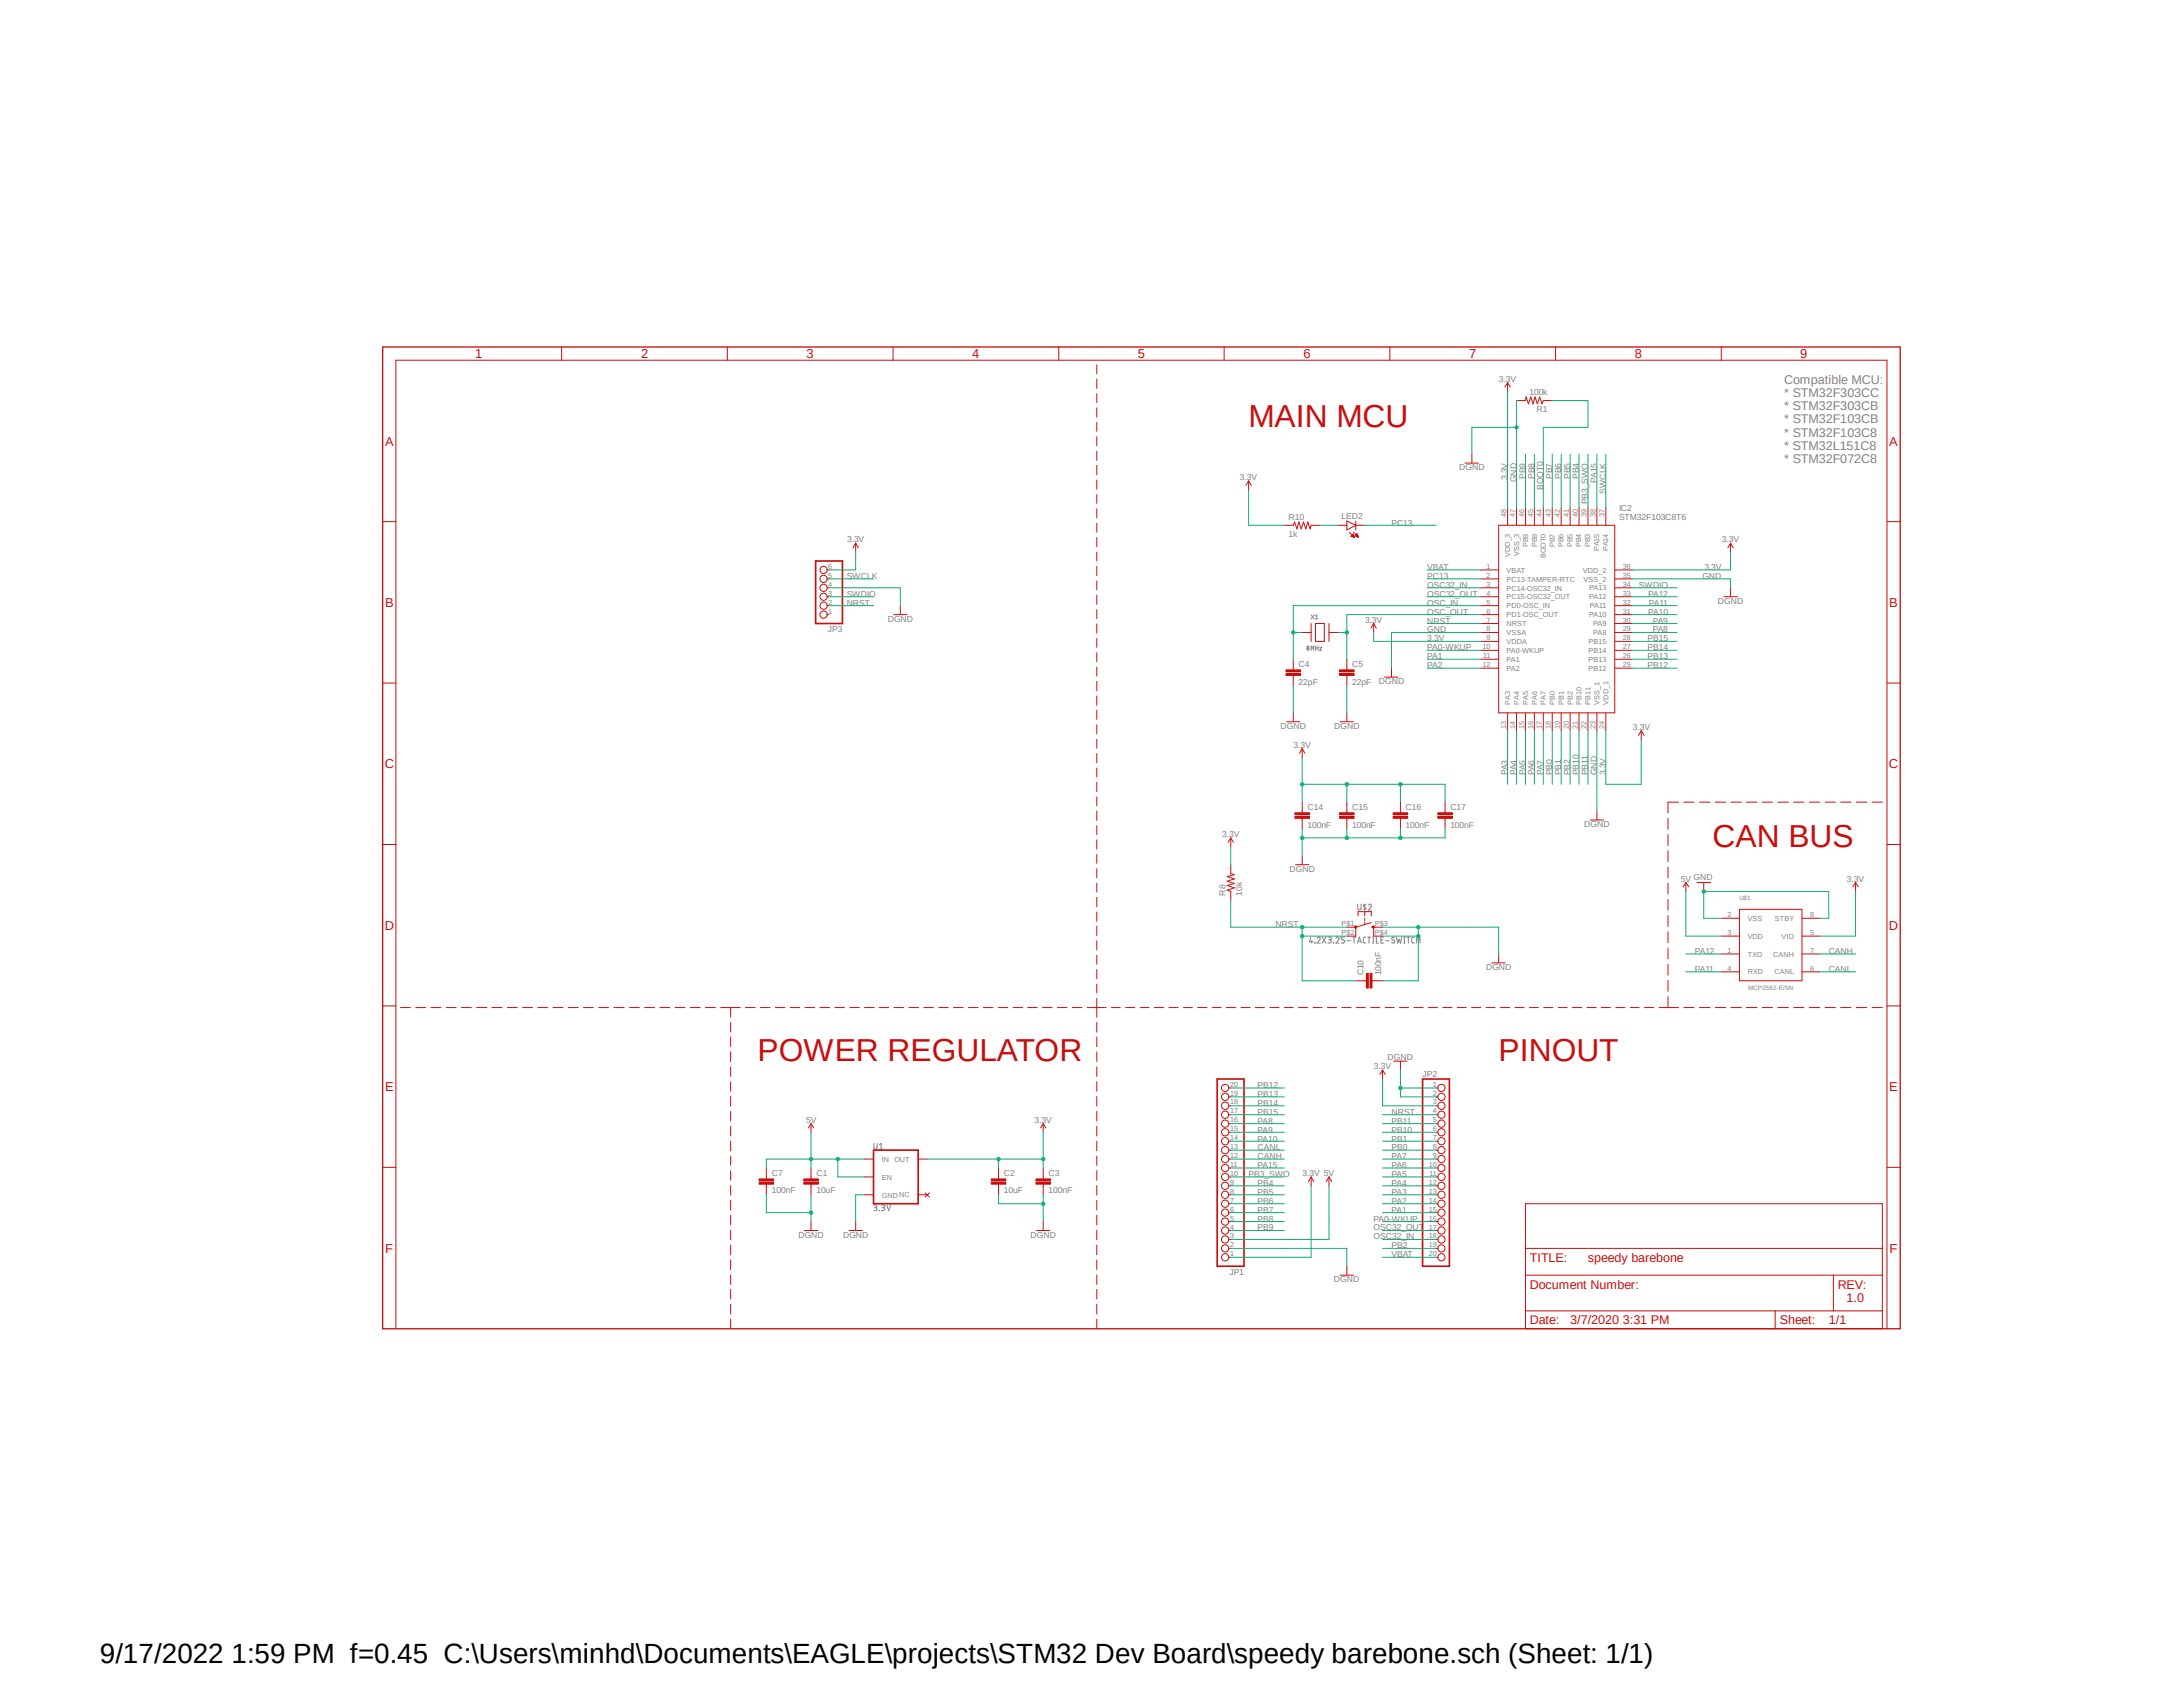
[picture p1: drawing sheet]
<svg xmlns="http://www.w3.org/2000/svg" width="279mm" height="216mm" viewBox="0 0 279 216" stroke-linecap="round" stroke-linejoin="round" font-family="sans-serif">
<defs><g id="words">
<g font-size="4.1" fill="#c90d0c">
<text x="159.8" y="54.7">MAIN MCU</text>
<text x="219.2" y="108.4">CAN BUS</text>
<text x="96.9" y="135.8">POWER REGULATOR</text>
<text x="191.8" y="135.8">PINOUT</text>
</g>
<text font-size="3.6" x="12.8" y="212.9">9/17/2022 1:59 PM f=0.45 C:\Users\minhd\Documents\EAGLE\projects\STM32 Dev Board\speedy barebone.sch (Sheet: 1/1)</text>
<g font-size="1.7" fill="#c90d0c">
<text x="60.8" y="45.8">1</text>
<text x="82" y="45.8">2</text>
<text x="103.2" y="45.8">3</text>
<text x="124.4" y="45.8">4</text>
<text x="145.6" y="45.8">5</text>
<text x="166.8" y="45.8">6</text>
<text x="188" y="45.8">7</text>
<text x="209.3" y="45.8">8</text>
<text x="230.4" y="45.8">9</text>
<text x="49.3" y="57">A</text>
<text x="241.8" y="57">A</text>
<text x="49.3" y="77.7">B</text>
<text x="241.8" y="77.7">B</text>
<text x="49.2" y="98.3">C</text>
<text x="241.8" y="98.3">C</text>
<text x="49.2" y="119">D</text>
<text x="241.8" y="119">D</text>
<text x="49.3" y="139.7">E</text>
<text x="241.8" y="139.7">E</text>
<text x="49.3" y="160.3">F</text>
<text x="241.9" y="160.3">F</text>
</g>
<g font-size="1.6" fill="#808080">
<text x="228.3" y="49.1">Compatible MCU:</text>
<text x="228.3" y="50.8">* STM32F303CC</text>
<text x="228.3" y="52.5">* STM32F303CB</text>
<text x="228.3" y="54.2">* STM32F103CB</text>
<text x="228.3" y="55.9">* STM32F103C8</text>
<text x="228.3" y="57.6">* STM32L151C8</text>
<text x="228.3" y="59.3">* STM32F072C8</text>
</g>
<g font-size="1.6" fill="#c90d0c">
<text x="195.8" y="161.5">TITLE:</text>
<text x="203.2" y="161.5">speedy barebone</text>
<text x="195.8" y="164.9">Document Number:</text>
<text x="235.2" y="164.9">REV:</text>
<text x="236.4" y="166.6">1.0</text>
<text x="195.8" y="169.5">Date:</text>
<text x="201" y="169.5">3/7/2020 3:31 PM</text>
<text x="227.8" y="169.5">Sheet:</text>
<text x="234.1" y="169.5">1/1</text>
</g>
<g font-size="1.1" fill="#808080">
<text x="191.8" y="48.9">3.3V</text>
<text x="195.7" y="50.6">100k</text>
<text x="196.7" y="52.7">R1</text>
<text x="158.7" y="61.4">3.3V</text>
<text x="186.8" y="60.2">DGND</text>
<text x="193" y="61.5" transform="rotate(-90 193 61.5)">3.3V</text>
<text x="194.1" y="61.7" transform="rotate(-90 194.1 61.7)">GND</text>
<text x="195.2" y="61.3" transform="rotate(-90 195.2 61.3)">PB9</text>
<text x="196.4" y="61.3" transform="rotate(-90 196.4 61.3)">PB8</text>
<text x="197.5" y="62.7" transform="rotate(-90 197.5 62.7)">BOOT0</text>
<text x="198.7" y="61.3" transform="rotate(-90 198.7 61.3)">PB7</text>
<text x="199.8" y="61.3" transform="rotate(-90 199.8 61.3)">PB6</text>
<text x="201" y="61.3" transform="rotate(-90 201 61.3)">PB5</text>
<text x="202.1" y="61.3" transform="rotate(-90 202.1 61.3)">PB4</text>
<text x="203.2" y="64.6" transform="rotate(-90 203.2 64.6)">PB3_SWO</text>
<text x="204.4" y="61.8" transform="rotate(-90 204.4 61.8)">PA15</text>
<text x="205.5" y="63.2" transform="rotate(-90 205.5 63.2)">SWCLK</text>
<text x="207.2" y="65.4">IC2</text>
<text x="108.4" y="69.4">3.3V</text>
<text x="164.9" y="68.7">1k</text>
<text x="164.9" y="66.6">R10</text>
<text x="171.7" y="66.5">LED2</text>
<text x="178.1" y="67.3">PC13</text>
<text x="207.2" y="66.5">STM32F103C8T6</text>
<text x="220.4" y="69.4">3.3V</text>
<text x="108.4" y="77.5">NRST</text>
<text x="108.4" y="76.4">SWDIO</text>
<text x="108.4" y="74.1">SWCLK</text>
<text x="182.7" y="72.9">VBAT</text>
<text x="182.7" y="74.1">PC13</text>
<text x="182.7" y="75.2">OSC32_IN</text>
<text x="182.7" y="76.4">OSC32_OUT</text>
<text x="182.7" y="77.5">OSC_IN</text>
<text x="209.8" y="75.2">SWDIO</text>
<text x="210.9" y="76.4">PA12</text>
<text x="211" y="77.5">PA11</text>
<text x="217.9" y="74.1">GND</text>
<text x="218.1" y="72.9">3.3V</text>
<text x="219.9" y="77.3">DGND</text>
<text x="106" y="80.9">JP3</text>
<text x="113.6" y="79.6">DGND</text>
<text x="174.7" y="79.7">3.3V</text>
<text x="182.7" y="78.7">OSC_OUT</text>
<text x="182.7" y="79.8">NRST</text>
<text x="182.7" y="83.2">PA0-WKUP</text>
<text x="182.7" y="80.9">GND</text>
<text x="182.7" y="82.1">3.3V</text>
<text x="210.9" y="82.1">PB15</text>
<text x="210.9" y="83.2">PB14</text>
<text x="210.9" y="78.7">PA10</text>
<text x="211.5" y="79.8">PA9</text>
<text x="211.5" y="80.9">PA8</text>
<text x="166.2" y="87.6">22pF</text>
<text x="166.2" y="85.3">C4</text>
<text x="173.1" y="87.6">22pF</text>
<text x="173.1" y="85.3">C5</text>
<text x="176.5" y="87.6">DGND</text>
<text x="182.7" y="84.4">PA1</text>
<text x="182.7" y="85.5">PA2</text>
<text x="210.9" y="84.4">PB13</text>
<text x="210.9" y="85.5">PB12</text>
<text x="163.9" y="93.3">DGND</text>
<text x="165.6" y="95.7">3.3V</text>
<text x="170.8" y="93.3">DGND</text>
<text x="209" y="93.4">3.3V</text>
<text x="193" y="99.2" transform="rotate(-90 193 99.2)">PA3</text>
<text x="194.1" y="99.2" transform="rotate(-90 194.1 99.2)">PA4</text>
<text x="195.2" y="99.2" transform="rotate(-90 195.2 99.2)">PA5</text>
<text x="196.4" y="99.2" transform="rotate(-90 196.4 99.2)">PA6</text>
<text x="197.5" y="99.2" transform="rotate(-90 197.5 99.2)">PA7</text>
<text x="198.7" y="99.2" transform="rotate(-90 198.7 99.2)">PB0</text>
<text x="199.8" y="99.2" transform="rotate(-90 199.8 99.2)">PB1</text>
<text x="201" y="99.2" transform="rotate(-90 201 99.2)">PB2</text>
<text x="202.1" y="99.2" transform="rotate(-90 202.1 99.2)">PB10</text>
<text x="203.2" y="99.2" transform="rotate(-90 203.2 99.2)">PB11</text>
<text x="204.4" y="99.2" transform="rotate(-90 204.4 99.2)">GND</text>
<text x="205.5" y="99.2" transform="rotate(-90 205.5 99.2)">3.3V</text>
<text x="156.4" y="107.1">3.3V</text>
<text x="167.3" y="105.9">100nF</text>
<text x="167.3" y="103.6">C14</text>
<text x="173.1" y="105.9">100nF</text>
<text x="173.1" y="103.6">C15</text>
<text x="179.9" y="105.9">100nF</text>
<text x="179.9" y="103.6">C16</text>
<text x="185.6" y="105.9">100nF</text>
<text x="185.6" y="103.6">C17</text>
<text x="202.8" y="105.9">DGND</text>
<text x="165.1" y="111.6">DGND</text>
<text x="215.1" y="112.8">5V GND</text>
<text x="236.4" y="112.8">3.3V</text>
<text x="156.8" y="114.6" transform="rotate(-90 156.8 114.6)">R8</text>
<text x="159" y="114.6" transform="rotate(-90 159 114.6)">10k</text>
<text x="163.2" y="118.7">NRST</text>
<text x="174.5" y="124.8" transform="rotate(-90 174.5 124.8)">C10</text>
<text x="176.8" y="124.8" transform="rotate(-90 176.8 124.8)">100nF</text>
<text x="190.2" y="124.1">DGND</text>
<text x="216.9" y="122.1">PA12</text>
<text x="216.9" y="124.4">PA11</text>
<text x="234.1" y="122.1">CANH</text>
<text x="234.1" y="124.4">CANL</text>
<text x="175.8" y="136.8">3.3V</text>
<text x="177.6" y="135.7">DGND</text>
<text x="182.1" y="137.8">JP2</text>
<text x="103.2" y="143.7">5V</text>
<text x="132.4" y="143.7">3.3V</text>
<text x="160.9" y="143.8">PA8</text>
<text x="160.9" y="142.7">PB15</text>
<text x="160.9" y="141.5">PB14</text>
<text x="160.9" y="140.4">PB13</text>
<text x="160.9" y="139.2">PB12</text>
<text x="178.1" y="142.7">NRST</text>
<text x="178.1" y="143.8">PB11</text>
<text x="160.9" y="146.1">PA10</text>
<text x="160.9" y="144.9">PA9</text>
<text x="160.9" y="149.5">PA15</text>
<text x="160.9" y="148.3">CANH</text>
<text x="160.9" y="147.2">CANL</text>
<text x="178.1" y="149.5">PA6</text>
<text x="178.1" y="148.3">PA7</text>
<text x="178.1" y="147.2">PB0</text>
<text x="178.1" y="146.1">PB1</text>
<text x="178.1" y="144.9">PB10</text>
<text x="98.8" y="152.7">100nF</text>
<text x="98.8" y="150.4">C7</text>
<text x="104.5" y="152.7">10uF</text>
<text x="104.5" y="150.4">C1</text>
<text x="128.5" y="150.4">C2</text>
<text x="128.5" y="152.7">10uF</text>
<text x="134.2" y="152.7">100nF</text>
<text x="134.2" y="150.4">C3</text>
<text x="159.8" y="150.6">PB3_SWO</text>
<text x="160.9" y="155.2">PB7</text>
<text x="160.9" y="154">PB6</text>
<text x="160.9" y="152.9">PB5</text>
<text x="160.9" y="151.8">PB4</text>
<text x="166.7" y="150.5">3.3V 5V</text>
<text x="178.1" y="155.2">PA1</text>
<text x="178.1" y="154">PA2</text>
<text x="178.1" y="152.9">PA3</text>
<text x="178.1" y="151.8">PA4</text>
<text x="178.1" y="150.6">PA5</text>
<text x="102.2" y="158.4">DGND</text>
<text x="107.9" y="158.4">DGND</text>
<text x="131.9" y="158.4">DGND</text>
<text x="160.9" y="157.5">PB9</text>
<text x="160.9" y="156.3">PB8</text>
<text x="175.8" y="158.6">OSC32_IN</text>
<text x="175.8" y="157.5">OSC32_OUT</text>
<text x="175.8" y="156.3">PA0-WKUP</text>
<text x="178.1" y="160.9">VBAT</text>
<text x="178.1" y="159.8">PB2</text>
<text x="157.3" y="163.1">JP1</text>
<text x="170.7" y="164.1">DGND</text>
</g>
<g font-size=".9" fill="#808080">
<text x="192.8" y="66.2" transform="rotate(-90 192.8 66.2)">48</text>
<text x="193.3" y="71.3" transform="rotate(-90 193.3 71.3)">VDD_3</text>
<text x="193.9" y="66.2" transform="rotate(-90 193.9 66.2)">47</text>
<text x="194.4" y="71.2" transform="rotate(-90 194.4 71.2)">VSS_3</text>
<text x="195.1" y="66.2" transform="rotate(-90 195.1 66.2)">46</text>
<text x="195.6" y="70.1" transform="rotate(-90 195.6 70.1)">PB9</text>
<text x="196.2" y="66.2" transform="rotate(-90 196.2 66.2)">45</text>
<text x="196.7" y="70.1" transform="rotate(-90 196.7 70.1)">PB8</text>
<text x="197.4" y="66.2" transform="rotate(-90 197.4 66.2)">44</text>
<text x="197.9" y="71.5" transform="rotate(-90 197.9 71.5)">BOOT0</text>
<text x="198.5" y="66.2" transform="rotate(-90 198.5 66.2)">43</text>
<text x="199" y="70.1" transform="rotate(-90 199 70.1)">PB7</text>
<text x="199.6" y="66.2" transform="rotate(-90 199.6 66.2)">42</text>
<text x="200.1" y="70.1" transform="rotate(-90 200.1 70.1)">PB6</text>
<text x="200.8" y="66.2" transform="rotate(-90 200.8 66.2)">41</text>
<text x="201.2" y="70.1" transform="rotate(-90 201.2 70.1)">PB5</text>
<text x="201.9" y="66.2" transform="rotate(-90 201.9 66.2)">40</text>
<text x="202.4" y="70.1" transform="rotate(-90 202.4 70.1)">PB4</text>
<text x="203.1" y="66.2" transform="rotate(-90 203.1 66.2)">39</text>
<text x="203.5" y="70.1" transform="rotate(-90 203.5 70.1)">PB3</text>
<text x="204.2" y="66.2" transform="rotate(-90 204.2 66.2)">38</text>
<text x="204.7" y="70.5" transform="rotate(-90 204.7 70.5)">PA15</text>
<text x="205.4" y="66.2" transform="rotate(-90 205.4 66.2)">37</text>
<text x="205.8" y="70.5" transform="rotate(-90 205.8 70.5)">PA14</text>
<text x="106" y="77.4">2</text>
<text x="106" y="76.2">3</text>
<text x="106" y="75.1">4</text>
<text x="106" y="74">5</text>
<text x="106" y="72.8">6</text>
<text x="190.2" y="72.8">1</text>
<text x="190.2" y="74">2</text>
<text x="190.2" y="75.1">3</text>
<text x="190.2" y="76.2">4</text>
<text x="190.2" y="77.4">5</text>
<text x="192.8" y="73.3">VBAT</text>
<text x="192.8" y="74.5">PC13-TAMPER-RTC</text>
<text x="192.8" y="75.6">PC14-OSC32_IN</text>
<text x="192.8" y="76.7">PC15-OSC32_OUT</text>
<text x="192.8" y="77.8">PD0-OSC_IN</text>
<text x="202.6" y="73.3">VDD_2</text>
<text x="202.7" y="74.4">VSS_2</text>
<text x="203.4" y="75.6">PA13</text>
<text x="203.4" y="76.7">PA12</text>
<text x="203.5" y="77.8">PA11</text>
<text x="207.7" y="72.8">36</text>
<text x="207.7" y="74">35</text>
<text x="207.7" y="75.1">34</text>
<text x="207.7" y="76.2">33</text>
<text x="207.7" y="77.4">32</text>
<text x="106" y="78.5">1</text>
<text x="189.7" y="83.1">10</text>
<text x="190.2" y="78.5">6</text>
<text x="190.2" y="79.7">7</text>
<text x="190.2" y="80.8">8</text>
<text x="190.2" y="82">9</text>
<text x="192.8" y="79">PD1-OSC_OUT</text>
<text x="192.8" y="80.1">NRST</text>
<text x="192.8" y="81.3">VSSA</text>
<text x="192.8" y="82.4">VDDA</text>
<text x="192.8" y="83.6">PA0-WKUP</text>
<text x="203.3" y="82.4">PB15</text>
<text x="203.3" y="83.6">PB14</text>
<text x="203.4" y="79">PA10</text>
<text x="203.9" y="80.1">PA9</text>
<text x="203.9" y="81.3">PA8</text>
<text x="207.7" y="78.5">31</text>
<text x="207.7" y="79.7">30</text>
<text x="207.7" y="80.8">29</text>
<text x="207.7" y="82">28</text>
<text x="207.7" y="83.1">27</text>
<text x="189.7" y="85.3">12</text>
<text x="189.8" y="84.2">11</text>
<text x="192.8" y="84.7">PA1</text>
<text x="192.8" y="85.9">PA2</text>
<text x="203.3" y="84.7">PB13</text>
<text x="203.3" y="85.9">PB12</text>
<text x="207.7" y="84.2">26</text>
<text x="207.7" y="85.3">25</text>
<text x="192.8" y="93.3" transform="rotate(-90 192.8 93.3)">13</text>
<text x="193.3" y="90.2" transform="rotate(-90 193.3 90.2)">PA3</text>
<text x="193.9" y="93.3" transform="rotate(-90 193.9 93.3)">14</text>
<text x="194.4" y="90.2" transform="rotate(-90 194.4 90.2)">PA4</text>
<text x="195.1" y="93.3" transform="rotate(-90 195.1 93.3)">15</text>
<text x="195.6" y="90.2" transform="rotate(-90 195.6 90.2)">PA5</text>
<text x="196.2" y="93.3" transform="rotate(-90 196.2 93.3)">16</text>
<text x="196.7" y="90.2" transform="rotate(-90 196.7 90.2)">PA6</text>
<text x="197.4" y="93.3" transform="rotate(-90 197.4 93.3)">17</text>
<text x="197.9" y="90.2" transform="rotate(-90 197.9 90.2)">PA7</text>
<text x="198.5" y="93.3" transform="rotate(-90 198.5 93.3)">18</text>
<text x="199" y="90.2" transform="rotate(-90 199 90.2)">PB0</text>
<text x="199.6" y="93.3" transform="rotate(-90 199.6 93.3)">19</text>
<text x="200.1" y="90.2" transform="rotate(-90 200.1 90.2)">PB1</text>
<text x="200.8" y="93.3" transform="rotate(-90 200.8 93.3)">20</text>
<text x="201.3" y="90.2" transform="rotate(-90 201.3 90.2)">PB2</text>
<text x="201.9" y="93.3" transform="rotate(-90 201.9 93.3)">21</text>
<text x="202.4" y="90.2" transform="rotate(-90 202.4 90.2)">PB10</text>
<text x="203.1" y="93.3" transform="rotate(-90 203.1 93.3)">22</text>
<text x="203.6" y="90.2" transform="rotate(-90 203.6 90.2)">PB11</text>
<text x="204.2" y="93.3" transform="rotate(-90 204.2 93.3)">23</text>
<text x="204.7" y="90.2" transform="rotate(-90 204.7 90.2)">VSS_1</text>
<text x="205.4" y="93.3" transform="rotate(-90 205.4 93.3)">24</text>
<text x="205.9" y="90.2" transform="rotate(-90 205.9 90.2)">VDD_1</text>
<text x="171.7" y="118.5">P$1</text>
<text x="171.7" y="119.6">P$2</text>
<text x="176" y="118.5">P$3</text>
<text x="176" y="119.6">P$4</text>
<text x="221.1" y="117.3">2</text>
<text x="221.1" y="119.6">3</text>
<text x="223.7" y="117.9">VSS</text>
<text x="227.2" y="117.9">STBY</text>
<text x="231.7" y="119.6">5</text>
<text x="231.7" y="117.3">8</text>
<text x="221.1" y="121.9">1</text>
<text x="221.1" y="124.2">4</text>
<text x="223.7" y="122.4">TXD</text>
<text x="223.7" y="120.1">VDD</text>
<text x="223.7" y="124.7">RXD</text>
<text x="226.9" y="122.4">CANH</text>
<text x="227.1" y="124.7">CANL</text>
<text x="228" y="120.1">VIO</text>
<text x="231.7" y="124.2">6</text>
<text x="231.7" y="121.9">7</text>
<text x="157.4" y="143.6">16</text>
<text x="157.4" y="142.5">17</text>
<text x="157.4" y="141.3">18</text>
<text x="157.4" y="140.2">19</text>
<text x="157.4" y="139.1">20</text>
<text x="183.4" y="139.1">1</text>
<text x="183.4" y="140.2">2</text>
<text x="183.4" y="141.3">3</text>
<text x="183.4" y="142.5">4</text>
<text x="183.4" y="143.6">5</text>
<text x="112.9" y="148.7">IN</text>
<text x="114.5" y="148.7">OUT</text>
<text x="157.4" y="149.3">11</text>
<text x="157.4" y="148.2">12</text>
<text x="157.4" y="147.1">13</text>
<text x="157.4" y="145.9">14</text>
<text x="157.4" y="144.8">15</text>
<text x="182.9" y="149.3">10</text>
<text x="183.4" y="144.8">6</text>
<text x="183.4" y="145.9">7</text>
<text x="183.4" y="147.1">8</text>
<text x="183.4" y="148.2">9</text>
<text x="112.9" y="153.3">GND NC</text>
<text x="112.9" y="151">EN</text>
<text x="157.4" y="155.1">6</text>
<text x="157.4" y="153.9">7</text>
<text x="157.4" y="152.8">8</text>
<text x="157.4" y="151.6">9</text>
<text x="157.4" y="150.5">10</text>
<text x="182.9" y="151.6">12</text>
<text x="182.9" y="152.8">13</text>
<text x="182.9" y="153.9">14</text>
<text x="182.9" y="155.1">15</text>
<text x="183" y="150.5">11</text>
<text x="157.4" y="160.8">1</text>
<text x="157.4" y="159.6">2</text>
<text x="157.4" y="158.5">3</text>
<text x="157.4" y="157.4">4</text>
<text x="157.4" y="156.2">5</text>
<text x="182.9" y="156.2">16</text>
<text x="182.9" y="157.4">17</text>
<text x="182.9" y="158.5">18</text>
<text x="182.9" y="159.6">19</text>
<text x="182.9" y="160.8">20</text>
</g>
<g font-size=".8" fill="#808080">
<text x="222.6" y="115.2">U$1</text>
<text x="223.8" y="126.7">MCP2562-E/SN</text>
</g>
</g></defs>
<path d="M48.7 44.2l194.7 126.1M243.4 44.2l-194.7 126.1" fill="none" stroke="#fff" stroke-width=".13"/>
<g fill="none" stroke="#808080" stroke-width=".13">
<path d="M167.8 78.7l.4 .5M168.2 78.7l-.4 .5M168.4 78.8l.1-.1v.5M168.4 79.2h.3M167.3 82.9l.3 .2-.2 .1-.1-.1zM167.8 83.2v-.5l.2 .3 .1-.3v.5M168.4 82.7v.5M168.4 82.9h.3M168.7 82.7v.5M168.9 82.8h.3l-.3 .4h.3M167.8 119.9l-.2 .6h.4M169.2 119.9l.5 .8"/>
<path d="M169.7 119.9l-.5 .8M170 119.9h.2l.2 .2-.1 .1-.2 .1M172.1 119.9h-.4v.4h.2l.2 .1-.1 .2-.3 .1M173.1 119.9h.4M173.3 119.9v.8M173.8 115.7v.5l.1 .3 .3-.1v-.2v-.5M174.7 115.7v.8M174.8 119.9l-.3 .1v.1v.5l.3 .1M174.8 115.8h-.2l-.1 .1 .3 .4-.1 .1-.2-.1M175 119.9h.4M175.1 115.9l.2-.2 .2 .1v.2l-.4 .5h.4M175.2 119.9v.8"/>
<path d="M175.7 119.9h.1M175.8 119.9v.8M176.1 119.9v.8h.3M177.1 119.9h-.4v.8h.4M178.7 119.9l.2 .8 .2-.5 .1 .5 .2-.8M179.7 119.9h.1M179.7 119.9v.8M180 119.9h.5M180.3 119.9v.8M181 119.9l-.2 .1-.1 .1v.5l.3 .1M181.3 119.9v.8M181.7 119.9v.8"/>
<path d="M167.9 120.4v.3M168.3 120.6h.1M168.6 120.1l.2-.2 .2 .1v.1l-.4 .6h.4M170.2 120.3l.2 .1v.1l-.1 .1-.3 .1M170.6 120.6h.1M171 120.1l.2-.2 .2 .1-.1 .3-.3 .4h.4M172.4 120.4h.5M173.7 120.7l.3-.8 .2 .8M173.8 120.5h.4M175.7 120.7h.1M176.7 120.3h.3M177.3 120.4h.5"/>
<path d="M178.5 120l-.2-.1-.2 .1 .1 .3 .2 .1 .1 .2-.1 .1-.3-.1M179.7 120.7h.1M181.3 120.3h.4M111.8 154.2h.3l.1 .1v.2l-.3 .1M111.8 146.3v.6l.2 .2 .2-.1 .1-.7M112.1 154.6h.1v.3h-.4M112.5 154.9h.1M112.6 146.5l.2-.2v.8M112.6 147.1h.4M112.8 154.2h.3l.1 .1v.2l-.3 .1M113 154.6h.2v.2l-.4 .1M113.5 154.2l.2 .7 .3-.7"/>
<circle cx="167.4" cy="82.8" r=".13"/>
</g>
<g fill="none" stroke="#c90d0c" stroke-width=".13">
<path d="M140.4 46.7v1.1M140.4 48.5v1.2M140.4 50.4v1.1M140.4 52.2v1.2M140.4 54.1v1.1M140.4 55.9v1.2M140.4 57.7v1.2M140.4 59.6v1.1M187.5 59.3h1.7M188.4 58.1v1.2M193 49v1.1M193 49l.3 .5"/>
<path d="M193 49l-.4 .5M140.4 61.4v1.2M140.4 63.3v1.1M140.4 65.1v1.2M140.4 67v1.1M140.4 68.8v1.2M140.4 70.7v1.1M140.4 72.5v1.2M140.4 74.3v1.2M140.4 76.2v1.1M140.4 78v1.2M140.4 79.8v1.2"/>
<path d="M189.5 72.9h2.3M189.5 74.1h2.3M189.5 75.2h2.3M189.5 76.4h2.3M189.5 77.5h2.3M189.5 78.7h2.3M189.5 79.8h2.3M191.8 67.2h14.9v24h-14.9zM193 65v2.2M194.1 65v2.2M195.2 65v2.2M196.4 65v2.2"/>
<path d="M197.5 65v2.2M198.7 65v2.2M199.8 65v2.2M201 65v2.2M202.1 65v2.2M203.2 65v2.2M204.4 65v2.2M205.5 65v2.2M206.7 72.9h2.2M206.7 74.1h2.2M206.7 75.2h2.2M206.7 76.4h2.2"/>
<path d="M206.7 77.5h2.2M206.7 78.7h2.2M206.7 79.8h2.2M220.6 76.4h1.8M221.5 69.5l.3 .6M221.5 69.5l-.4 .6M221.5 69.5v1.2M221.5 75.2v1.2M140.4 81.7v1.1M140.4 83.5v1.2M140.4 85.4v1.1M140.4 87.2v1.2"/>
<path d="M140.4 89.1v1.2M140.4 90.9v1.2M140.4 92.8v1.1M140.4 94.6v1.2M140.4 96.4v1.2M140.4 98.3v1.1M189.5 80.9h2.3M189.5 82.1h2.3M189.5 83.2h2.3M189.5 84.4h2.3M189.5 85.5h2.3M193 91.2v2.3"/>
<path d="M194.1 91.2v2.3M195.2 91.2v2.3M196.4 91.2v2.3M197.5 91.2v2.3M198.7 91.2v2.3M199.8 91.2v2.3M201 91.2v2.3M202.1 91.2v2.3M203.2 91.2v2.3M204.4 91.2v2.3M205.5 91.2v2.3M206.7 80.9h2.2"/>
<path d="M206.7 82.1h2.2M206.7 83.2h2.2M206.7 84.4h2.2M206.7 85.5h2.2M210.1 93.5l.3 .6M210.1 93.5l-.4 .6M210.1 93.5v1.2M140.4 100.1v1.2M140.4 102v1.1M140.4 103.8v1.2M140.4 105.7v1.1M140.4 107.5v1.2"/>
<path d="M140.4 109.3v1.2M140.4 111.2v1.2M140.4 113v1.2M140.4 114.9v1.1M140.4 116.7v1.2M140.4 118.5v1.2M203.5 104.9h1.7M204.4 103.8v1.1M213.5 104.7v1.4M213.5 106.8v1.4M213.5 108.9v1.4M213.5 111v1.4"/>
<path d="M213.5 113v1.4M213.5 115.1v1.4M213.5 117.2v1.4M213.5 119.3v1.3M214.8 102.7h-1.3v1.4M215.5 102.7h1.3M217.5 102.7h1.4M219.5 102.7h1.4M221.5 102.7h1.4M223.5 102.7h1.4M225.6 102.7h1.3M227.5 102.7h1.4"/>
<path d="M229.6 102.7h1.3M231.6 102.7h1.3M233.6 102.7h1.3M235.6 102.7h1.3M237.6 102.7h1.3M239.6 102.7h1.3M51.3 128.9h1.2M53.2 128.9h1.3M55.2 128.9h1.2M57.1 128.9h1.3M59.1 128.9h1.2M61 128.9h1.3"/>
<path d="M62.9 128.9h1.4M64.9 128.9h1.3M66.9 128.9h1.3M68.8 128.9h1.3M70.8 128.9h1.3M72.7 128.9h1.3M74.7 128.9h1.2M76.6 128.9h1.3M78.6 128.9h1.3M80.6 128.9h1.2M82.5 128.9h1.3M84.5 128.9h1.2"/>
<path d="M86.4 128.9h1.3M88.3 128.9h1.3M90.3 128.9h1.3M92.2 128.9h2.5M93.5 128.9v1.3M93.5 130.9v1.2M93.5 132.7v1.2M93.5 134.6v1.2M93.5 136.5v1.3M93.5 138.4v1.3M95.4 128.9h1.2M97.3 128.9h1.3"/>
<path d="M99.2 128.9h1.3M101.1 128.9h1.3M103 128.9h1.3M104.9 128.9h1.3M106.8 128.9h1.3M108.8 128.9h1.2M110.7 128.9h1.2M112.5 128.9h1.2M114.4 128.9h1.3M116.3 128.9h1.3M118.2 128.9h1.3M120.1 128.9h1.3"/>
<path d="M122 128.9h1.3M124 128.9h1.2M125.9 128.9h1.2M127.8 128.9h1.2M129.7 128.9h1.2M131.5 128.9h1.3M133.4 128.9h1.3M135.3 128.9h1.3M137.2 128.9h1.3M139.1 128.9h2.5M140.4 120.4v1.2M140.4 122.3v1.1"/>
<path d="M140.4 124.1v1.2M140.4 125.9v1.2M140.4 127.8v2.4M140.4 130.9v1.2M140.4 132.7v1.2M140.4 134.6v1.2M140.4 136.5v1.3M140.4 138.4v1.3M142.2 128.9h1.2M144.1 128.9h1.1M145.9 128.9h1.2M147.7 128.9h1.2"/>
<path d="M149.6 128.9h1.2M151.5 128.9h1.1M153.3 128.9h1.2M155.2 128.9h1.1M157 128.9h1.2M157.3 139.2h.2M158.8 128.9h1.2M160.7 128.9h1.1M162.5 128.9h1.2M164.4 128.9h1.1M166.2 128.9h1.2M168.1 128.9h1.1"/>
<path d="M169.9 128.9h1.2M171.7 128.9h1.2M173.6 128.9h1.2M175.4 128.9h1.2M177.3 128.9h1.1M178.4 135.8h1.7M179.1 128.9h1.2M179.2 135.8v1.1M181 128.9h1.2M182.8 128.9h1.2M183.8 139.2h.3M184.7 128.9h1.1"/>
<path d="M186.5 128.9h1.2M188.3 128.9h1.2M190.2 128.9h1.1M192 128.9h1.2M193.9 128.9h1.2M195.7 128.9h1.2M197.6 128.9h1.2M199.4 128.9h1.2M201.3 128.9h1.1M203.1 128.9h1.2M204.9 128.9h1.2M206.8 128.9h1.2"/>
<path d="M208.7 128.9h1.1M210.5 128.9h1.2M212.3 128.9h2.5M213.5 121.3v1.4M213.5 123.4v1.4M213.5 125.5v1.4M213.5 127.6v1.3M215.5 128.9h1.3M217.5 128.9h1.4M219.5 128.9h1.4M221.5 128.9h1.4M223.5 128.9h1.4"/>
<path d="M225.6 128.9h1.3M227.5 128.9h1.4M229.6 128.9h1.3M231.6 128.9h1.3M233.6 128.9h1.3M235.6 128.9h1.3M237.6 128.9h1.3M239.6 128.9h1.3M93.5 140.3v1.3M93.5 142.2v1.3M93.5 144.1v1.3M93.5 146v1.3"/>
<path d="M93.5 148v1.1M93.5 149.8v1.2M93.5 151.7v1.3M93.5 153.6v1.3M93.5 155.5v1.3M93.5 157.4v1.3M93.5 159.3v1.3M103.8 150.6v.3M103.8 151.6v.2M110.7 152.9h1.1M110.7 150.6h1.1M110.7 148.3h1.1"/>
<path d="M117.5 152.9h1.2M117.5 148.3h1.2M118.4 152.7l.6 .5M119 152.7l-.6 .5M140.4 140.3v1.3M140.4 142.2v1.3M140.4 144.1v1.3M140.4 146v1.3M140.4 148v1.1M140.4 149.8v1.2M140.4 151.7v1.3M140.4 153.6v1.3"/>
<path d="M140.4 155.5v1.3M140.4 157.4v1.3M140.4 159.3v1.3M157.3 159.8h.2M157.3 158.6h.2M157.3 157.5h.2M157.3 156.3h.2M157.3 155.2h.2M157.3 154.1h.2M157.3 152.9h.2M157.3 151.8h.2M157.3 150.6h.2"/>
<path d="M157.3 149.5h.2M157.3 148.3h.2M157.3 147.2h.2M157.3 146h.2M157.3 144.9h.2M157.3 143.8h.2M157.3 142.7h.2M157.3 141.5h.2M157.3 140.4h.2M183.8 159.8h.3M183.8 158.6h.3M183.8 157.5h.3"/>
<path d="M183.8 156.3h.3M183.8 155.2h.3M183.8 154.1h.3M183.8 152.9h.3M183.8 151.8h.3M183.8 150.6h.3M183.8 149.5h.3M183.8 148.3h.3M183.8 147.2h.3M183.8 146h.3M183.8 144.9h.3M183.8 143.8h.3"/>
<path d="M183.8 142.7h.3M183.8 141.5h.3M183.8 140.4h.3M93.5 161.2v1.3M93.5 163.2v1.2M93.5 165v1.2M93.5 166.9v1.2M93.5 168.8v1.3M140.4 161.2v1.3M140.4 163.2v1.2M140.4 165v1.2M140.4 166.9v1.2"/>
<path d="M140.4 168.8v1.3M157.3 160.9h.2M183.8 160.9h.3"/>
<circle cx="156.8" cy="139.2" r=".46"/>
<circle cx="184.5" cy="139.2" r=".46"/>
<circle cx="156.8" cy="143.8" r=".46"/>
<circle cx="156.8" cy="141.5" r=".46"/>
<circle cx="156.8" cy="146.1" r=".46"/>
<circle cx="156.8" cy="152.9" r=".46"/>
<circle cx="156.8" cy="156.3" r=".46"/>
<circle cx="156.8" cy="151.8" r=".46"/>
<circle cx="156.8" cy="159.8" r=".46"/>
<circle cx="156.8" cy="157.5" r=".46"/>
<circle cx="156.8" cy="150.6" r=".46"/>
<circle cx="156.8" cy="148.3" r=".46"/>
<circle cx="156.8" cy="147.2" r=".46"/>
<circle cx="156.8" cy="158.6" r=".46"/>
<circle cx="156.8" cy="155.2" r=".46"/>
<circle cx="156.8" cy="140.4" r=".46"/>
<circle cx="156.8" cy="144.9" r=".46"/>
<circle cx="156.8" cy="149.5" r=".46"/>
<circle cx="156.8" cy="154.1" r=".46"/>
<circle cx="156.8" cy="142.7" r=".46"/>
<circle cx="184.5" cy="148.3" r=".46"/>
<circle cx="184.5" cy="144.9" r=".46"/>
<circle cx="184.5" cy="149.5" r=".46"/>
<circle cx="184.5" cy="143.8" r=".46"/>
<circle cx="184.5" cy="147.2" r=".46"/>
<circle cx="184.5" cy="154.1" r=".46"/>
<circle cx="184.5" cy="158.6" r=".46"/>
<circle cx="184.5" cy="159.8" r=".46"/>
<circle cx="184.5" cy="142.7" r=".46"/>
<circle cx="184.5" cy="151.8" r=".46"/>
<circle cx="184.5" cy="156.3" r=".46"/>
<circle cx="184.5" cy="140.4" r=".46"/>
<circle cx="184.5" cy="150.6" r=".46"/>
<circle cx="184.5" cy="146.1" r=".46"/>
<circle cx="184.5" cy="141.5" r=".46"/>
<circle cx="184.5" cy="155.2" r=".46"/>
<circle cx="184.5" cy="157.5" r=".46"/>
<circle cx="184.5" cy="152.9" r=".46"/>
<circle cx="156.8" cy="160.9" r=".46"/>
<circle cx="184.5" cy="160.9" r=".46"/>
</g>
<path d="M155.8 138.1h3.4v24h-3.4zM182.1 138.1h3.4v24h-3.4zM111.8 147.2h5.7v6.9h-5.7z" fill="none" stroke="#c90d0c" stroke-width=".21"/>
<path d="M102.9 151.3h1.8v.3h-1.8z" fill-rule="evenodd" fill="#c90d0c"/>
<path d="M102.9 151.3h1.8v.3h-1.8z" fill="none" stroke="#c90d0c" stroke-width=".13"/>
<path d="M102.9 150.9h1.8v.2h-1.8z" fill-rule="evenodd" fill="#c90d0c"/>
<path d="M102.9 150.9h1.8v.2h-1.8zM103.8 149.5v1.1M103.8 151.8v1.1M127.8 150.6v.3M127.8 151.6v.2" fill="none" stroke="#c90d0c" stroke-width=".13"/>
<path d="M126.9 151.3h1.8v.3h-1.8z" fill-rule="evenodd" fill="#c90d0c"/>
<path d="M126.9 151.3h1.8v.3h-1.8z" fill="none" stroke="#c90d0c" stroke-width=".13"/>
<path d="M126.9 150.9h1.8v.2h-1.8z" fill-rule="evenodd" fill="#c90d0c"/>
<path d="M126.9 150.9h1.8v.2h-1.8zM127.8 149.5v1.1M127.8 151.8v1.1M133.5 150.6v.3M133.5 151.6v.2" fill="none" stroke="#c90d0c" stroke-width=".13"/>
<path d="M132.6 151.3h1.9v.3h-1.9z" fill-rule="evenodd" fill="#c90d0c"/>
<path d="M132.6 151.3h1.9v.3h-1.9z" fill="none" stroke="#c90d0c" stroke-width=".13"/>
<path d="M132.6 150.9h1.9v.2h-1.9z" fill-rule="evenodd" fill="#c90d0c"/>
<g fill="none" stroke="#c90d0c" stroke-width=".13">
<path d="M167.8 79.8v2.3M168.4 79.8h1.1v2.3h-1.1zM170.1 79.8v2.3M175.8 79.8l.3 .6M175.8 79.8l-.3 .6M175.8 79.8v1.1M165.5 85.5v.3M165.5 86.4v.3M166.7 80.9h1.1M170.1 80.9h1.1M177.2 86.7h1.7M178.1 85.5v1.2"/>
<path d="M103 157.5h1.7M103.8 143.8l.3 .6M103.8 143.8l-.3 .6M103.8 143.8v1.1M103.8 156.3v1.2M132.6 150.9h1.9v.2h-1.9zM132.7 157.5h1.7M133.5 143.8v1.1M133.5 149.5v1.1M133.5 151.8v1.1M133.5 156.3v1.2M133.5 143.8l.4 .6"/>
<path d="M133.5 143.8l-.3 .6"/>
</g>
<path d="M164.6 86.2h1.9v.2h-1.9z" fill-rule="evenodd" fill="#c90d0c"/>
<path d="M164.6 86.2h1.9v.2h-1.9z" fill="none" stroke="#c90d0c" stroke-width=".13"/>
<path d="M164.6 85.7h1.9v.3h-1.9z" fill-rule="evenodd" fill="#c90d0c"/>
<path d="M164.6 85.7h1.9v.3h-1.9zM165.5 84.4v1.1M165.5 86.7v1.1M172.4 85.5v.3M172.4 86.4v.3" fill="none" stroke="#c90d0c" stroke-width=".13"/>
<path d="M171.4 86.2h1.9v.2h-1.9z" fill-rule="evenodd" fill="#c90d0c"/>
<path d="M171.4 86.2h1.9v.2h-1.9z" fill="none" stroke="#c90d0c" stroke-width=".13"/>
<path d="M171.4 85.7h1.9v.3h-1.9z" fill-rule="evenodd" fill="#c90d0c"/>
<g fill="none" stroke="#c90d0c" stroke-width=".13">
<path d="M164.7 92.4h1.7M165.5 91.2v1.2M171.4 85.7h1.9v.3h-1.9zM171.5 92.4h1.7M172.4 84.4v1.1M172.4 86.7v1.1M172.4 91.2v1.2M173.8 117.2v-.5h1.7v.5M174.7 116.7v.5M174.7 117.5v.3M174.7 118.1v.3M175.5 118.7h.3v1.1"/>
<path d="M175.5 118.1l-2 .6v1.1"/>
</g>
<path d="M173.4 118.5h.2v.2h-.2z" fill-rule="evenodd" fill="#c90d0c"/>
<path d="M173.4 118.5h.2v.2h-.2z" fill="none" stroke="#c90d0c" stroke-width=".13"/>
<path d="M175.7 118.5h.2v.2h-.2z" fill-rule="evenodd" fill="#c90d0c"/>
<path d="M157.5 110.7v1.1l.5 .1-.9 .3 .9 .3-.9 .3 .9 .3-.9 .2 .9 .3-.9 .3 .4 .2v1.1M172.4 118.7h1.1M172.4 119.8h1.1M175.7 118.5h.2v.2h-.2zM175.8 118.7h1.2M175.8 119.8h1.2M174.7 125.5h.2M175.6 125.5h.2" fill="none" stroke="#c90d0c" stroke-width=".13"/>
<path d="M175.3 124.6h.3v1.8h-.3z" fill-rule="evenodd" fill="#c90d0c"/>
<path d="M175.3 124.6h.3v1.8h-.3z" fill="none" stroke="#c90d0c" stroke-width=".13"/>
<path d="M174.9 124.6h.2v1.8h-.2z" fill-rule="evenodd" fill="#c90d0c"/>
<path d="M157.5 107.2l.4 .6M157.5 107.2l-.3 .6M157.5 107.2v1.2M166.7 103.8v.2M166.7 104.7v.2M173.5 125.5h1.2M174.9 124.6h.2v1.8h-.2zM175.8 125.5h1.2M190.9 123.2h1.8M191.8 122.1v1.1" fill="none" stroke="#c90d0c" stroke-width=".13"/>
<path d="M165.7 104.5h1.9v.2h-1.9z" fill-rule="evenodd" fill="#c90d0c"/>
<path d="M165.7 104.5h1.9v.2h-1.9z" fill="none" stroke="#c90d0c" stroke-width=".13"/>
<path d="M165.7 104h1.9v.3h-1.9z" fill-rule="evenodd" fill="#c90d0c"/>
<path d="M165.7 104h1.9v.3h-1.9zM166.7 102.7v1.1M166.7 104.9v1.2M172.4 103.8v.2M172.4 104.7v.2" fill="none" stroke="#c90d0c" stroke-width=".13"/>
<path d="M171.4 104.5h1.9v.2h-1.9z" fill-rule="evenodd" fill="#c90d0c"/>
<path d="M171.4 104.5h1.9v.2h-1.9z" fill="none" stroke="#c90d0c" stroke-width=".13"/>
<path d="M171.4 104h1.9v.3h-1.9z" fill-rule="evenodd" fill="#c90d0c"/>
<path d="M171.4 104h1.9v.3h-1.9zM172.4 102.7v1.1M172.4 104.9v1.2M179.2 103.8v.2M179.2 104.7v.2" fill="none" stroke="#c90d0c" stroke-width=".13"/>
<path d="M178.3 104.5h1.9v.2h-1.9z" fill-rule="evenodd" fill="#c90d0c"/>
<path d="M178.3 104.5h1.9v.2h-1.9z" fill="none" stroke="#c90d0c" stroke-width=".13"/>
<path d="M178.3 104h1.9v.3h-1.9z" fill-rule="evenodd" fill="#c90d0c"/>
<path d="M178.3 104h1.9v.3h-1.9zM179.2 102.7v1.1M179.2 104.9v1.2M185 103.8v.2M185 104.7v.2" fill="none" stroke="#c90d0c" stroke-width=".13"/>
<path d="M184 104.5h1.9v.2h-1.9z" fill-rule="evenodd" fill="#c90d0c"/>
<path d="M184 104.5h1.9v.2h-1.9z" fill="none" stroke="#c90d0c" stroke-width=".13"/>
<path d="M184 104h1.9v.3h-1.9z" fill-rule="evenodd" fill="#c90d0c"/>
<g fill="none" stroke="#c90d0c" stroke-width=".13">
<path d="M71.9 44.4v1.7M93.1 44.4v1.7M114.3 44.4v1.7M135.5 44.4v1.7M156.7 44.4v1.7M177.9 44.4v1.7M199.1 44.4v1.7M220.3 44.4v1.7M49 66.8h1.7M159.8 61.6l.3 .5M159.8 61.6l-.3 .5M159.8 61.6v1.1"/>
<path d="M164.4 67.2h1.1l.2-.4 .3 .9 .2-.9 .3 .9 .3-.9 .3 .9 .3-.9 .3 .9 .1-.5h1.2M171.2 67.2h1.2M172.4 66.7l1.1 .5-1.1 .6zM172.7 68.2l.7 .6M172.9 68.6l.5 .2M172.9 68.6l.3-.2 .2 .4M172.9 68.6h.4M173 68.6h.3M173 68.7h.3M173 68.5h.2M173.1 68.5h.1M173.1 68.4h.1"/>
<path d="M173.2 68.7h.1M173.2 68.1l.7 .6M173.3 68.7h.1M173.5 68.5h.3M173.5 66.7v1.1M173.5 67.2h1.2M173.5 68.6h.3M173.6 68.5h.1M173.6 68.6h.2M173.6 68.4h.1M173.7 68.7h.1M173.7 68.4h.1"/>
<path d="M173.7 68.3l-.3 .3 .5 .1M173.7 68.3l.2 .4M173.7 68.3v.1M173.8 68.7h.1M241.5 66.8h1.7M49 87.4h1.7M166.7 95.8v1.1M166.7 95.8l.3 .6M166.7 95.8l-.4 .6M241.5 87.4h1.7M49 108.1h1.7M165.8 110.7h1.7"/>
<path d="M166.7 109.5v1.2M184 104h1.9v.3h-1.9zM185 102.7v1.1M185 104.9v1.2M215.8 112.9l.4 .6M215.8 112.9l-.4 .6M215.8 112.9v1.2M217.2 112.9h1.7M218.1 112.9v1.2M220.3 117.5h2.3M220.3 119.8h2.3M222.6 116.4h8v9.1h-8z"/>
<path d="M230.6 117.5h2.3M230.6 119.8h2.3M237.5 112.9l-.3 .6M237.5 112.9l.3 .6M237.5 112.9v1.2M241.5 108.1h1.7M49 128.7h1.7M177 136.9l.3 .6M177 136.9l-.4 .6M177 136.9v1.2M220.3 122.1h2.3M220.3 124.4h2.3"/>
<path d="M230.6 122.1h2.3M230.6 124.4h2.3M241.5 128.7h1.7M49 149.4h1.7M98.1 150.6v.3M98.1 151.6v.2M108.7 157.5h1.7M109.5 156.3v1.2M167.8 150.6l-.3 .6M167.8 150.6l.3 .6M167.8 150.6v1.2M170.1 150.6l.3 .6"/>
<path d="M170.1 150.6l-.3 .6M170.1 150.6v1.2M195.2 154.1h45.7v16h-45.7zM195.2 159.8h45.7M241.5 149.4h1.7M50.7 170.1v-124h190.8v124M171.5 163.2h1.7M172.4 162.1v1.1M195.2 163.2h45.7M195.2 167.8h45.7M227.2 167.8v2.3M234.7 163.2v4.6"/>
</g>
<path d="M49 44.4h194.2v125.7h-194.2z" fill="none" stroke="#c90d0c" stroke-width=".17"/>
<path d="M97.2 151.3h1.8v.3h-1.8z" fill-rule="evenodd" fill="#c90d0c"/>
<path d="M97.2 151.3h1.8v.3h-1.8z" fill="none" stroke="#c90d0c" stroke-width=".13"/>
<path d="M97.2 150.9h1.8v.2h-1.8z" fill-rule="evenodd" fill="#c90d0c"/>
<g fill="none" stroke="#c90d0c" stroke-width=".13">
<path d="M194.1 51.3h1.1l.1-.5 .3 .9 .3-.9 .3 .9 .3-.9 .3 .9 .3-.9 .3 .9 .1-.4h1.2M105.8 78.7h.3M105.8 77.5h.3M105.8 76.4h.3M105.8 75.2h.3M105.8 74.1h.3M105.8 72.9h.3M109.5 69.5l.4 .6M109.5 69.5l-.3 .6M109.5 69.5v1.2M114.4 78.7h1.7M115.2 77.5v1.2"/>
<path d="M97.2 150.9h1.8v.2h-1.8zM98.1 149.5v1.1M98.1 151.8v1.1"/>
<circle cx="105.4" cy="75.2" r=".46"/>
<circle cx="105.4" cy="78.7" r=".46"/>
<circle cx="105.4" cy="74.1" r=".46"/>
<circle cx="105.4" cy="77.5" r=".46"/>
<circle cx="105.4" cy="76.4" r=".46"/>
<circle cx="105.4" cy="72.9" r=".46"/>
</g>
<path d="M104.4 71.8h3.4v8h-3.4z" fill="none" stroke="#c90d0c" stroke-width=".21"/>
<path d="M174.7 67.2h9.1M182.7 72.9h6.8M182.7 74.1h6.8M182.7 75.2h6.8M182.7 76.4h6.8M189.5 77.5h-24v6.9M165.5 80.9h1.2M177 158.6h6.8M177 157.5h6.8M177 160.9h6.8" fill="none" stroke="#0dab76" stroke-width=".13"/>
<circle cx="165.5" cy="80.9" r=".21" fill="#0dab76"/>
<g fill="none" stroke="#0dab76" stroke-width=".13">
<path d="M189.5 78.7h-17.1v5.7M171.2 80.9h1.2"/>
<circle cx="165.5" cy="80.9" r=".21"/>
</g>
<circle cx="172.4" cy="80.9" r=".21" fill="#0dab76"/>
<g fill="none" stroke="#0dab76" stroke-width=".13">
<path d="M182.7 79.8h6.8M157.5 115.2v3.5h14.9M166.7 118.7v1.1h5.7M177 142.7h6.8"/>
<circle cx="172.4" cy="80.9" r=".21"/>
</g>
<circle cx="166.7" cy="118.7" r=".21" fill="#0dab76"/>
<g fill="none" stroke="#0dab76" stroke-width=".13">
<path d="M166.7 119.8v5.7h6.8"/>
<circle cx="166.7" cy="118.7" r=".21"/>
</g>
<circle cx="166.7" cy="119.8" r=".21" fill="#0dab76"/>
<g fill="none" stroke="#0dab76" stroke-width=".13">
<path d="M195.2 58.1v6.9M196.4 58.1v6.9M198.7 58.1v6.9M199.8 58.1v6.9M201 58.1v6.9M202.1 58.1v6.9M203.2 58.1v6.9M204.4 58.1v6.9M205.5 58.1v6.9M106.1 77.5h5.7M106.1 76.4h5.7M106.1 74.1h5.7"/>
<path d="M208.9 77.5h5.7M208.9 75.2h5.7M208.9 76.4h5.7M208.9 78.7h5.7M208.9 79.8h5.7M182.7 83.2h6.8M182.7 84.4h6.8M182.7 85.5h6.8M193 93.5v6.9M194.1 93.5v6.9M195.2 93.5v6.9M196.4 93.5v6.9"/>
<path d="M197.5 93.5v6.9M198.7 93.5v6.9M199.8 93.5v6.9M201 93.5v6.9M202.1 93.5v6.9M203.2 93.5v6.9M208.9 83.2h5.7M208.9 84.4h5.7M208.9 85.5h5.7M208.9 80.9h5.7M208.9 82.1h5.7M157.5 139.2h6.9"/>
<path d="M183.8 139.2h-4.6v1.2h4.6M215.8 122.1h4.5M215.8 124.4h4.5M157.5 156.3h6.9M157.5 155.2h6.9M157.5 154.1h6.9M157.5 152.9h6.9M157.5 151.8h6.9M157.5 150.6h6.9M157.5 149.5h6.9M157.5 146h6.9M157.5 144.9h6.9"/>
<path d="M157.5 143.8h6.9M157.5 142.7h6.9M157.5 141.5h6.9M157.5 140.4h6.9M157.5 157.5h6.9M177 156.3h6.8M177 155.2h6.8M177 154.1h6.8M177 152.9h6.8M177 151.8h6.8M177 150.6h6.8M177 149.5h6.8"/>
<path d="M177 148.3h6.8M177 147.2h6.8M177 146h6.8M177 159.8h6.8M177 144.9h6.8M177 143.8h6.8"/>
<circle cx="166.7" cy="119.8" r=".21"/>
</g>
<circle cx="179.2" cy="139.2" r=".21" fill="#0dab76"/>
<g fill="none" stroke="#0dab76" stroke-width=".13">
<path d="M194.1 51.3v13.7M194.1 54.7h-5.7v3.4M208.9 74.1h12.6v1.1M204.4 93.5v10.3M179.2 136.9v2.3"/>
<circle cx="179.2" cy="139.2" r=".21"/>
</g>
<circle cx="194.1" cy="54.7" r=".21" fill="#0dab76"/>
<g fill="none" stroke="#0dab76" stroke-width=".13">
<path d="M98.1 152.9v2.3h5.7M103.8 152.9v3.4"/>
<circle cx="194.1" cy="54.7" r=".21"/>
</g>
<circle cx="103.8" cy="155.2" r=".21" fill="#0dab76"/>
<g fill="none" stroke="#0dab76" stroke-width=".13">
<path d="M127.8 152.9v1.2h5.7M133.5 152.9v3.4"/>
<circle cx="103.8" cy="155.2" r=".21"/>
</g>
<circle cx="133.5" cy="154" r=".21" fill="#0dab76"/>
<g fill="none" stroke="#0dab76" stroke-width=".13">
<path d="M165.5 87.8v3.4M172.4 87.8v3.4M189.5 80.9h-11.4v4.6M177 118.7h11.4M181.5 118.7v1.1h-4.5"/>
<circle cx="133.5" cy="154" r=".21"/>
</g>
<circle cx="181.5" cy="118.7" r=".21" fill="#0dab76"/>
<g fill="none" stroke="#0dab76" stroke-width=".13">
<path d="M181.5 119.8v5.7h-4.5"/>
<circle cx="181.5" cy="118.7" r=".21"/>
</g>
<circle cx="181.5" cy="119.8" r=".21" fill="#0dab76"/>
<g fill="none" stroke="#0dab76" stroke-width=".13">
<path d="M166.7 106.1v1.1h18.3v-1.1M179.2 106.1v1.1M188.4 118.7h3.4v3.4"/>
<circle cx="181.5" cy="119.8" r=".21"/>
</g>
<circle cx="179.2" cy="107.2" r=".21" fill="#0dab76"/>
<g fill="none" stroke="#0dab76" stroke-width=".13">
<path d="M172.4 106.1v1.1"/>
<circle cx="179.2" cy="107.2" r=".21"/>
</g>
<circle cx="172.4" cy="107.2" r=".21" fill="#0dab76"/>
<g fill="none" stroke="#0dab76" stroke-width=".13">
<path d="M166.7 107.2v2.3"/>
<circle cx="172.4" cy="107.2" r=".21"/>
</g>
<circle cx="166.7" cy="107.2" r=".21" fill="#0dab76"/>
<g fill="none" stroke="#0dab76" stroke-width=".13">
<path d="M220.3 117.5h-2.2v-3.4h16v3.4h-1.2M110.7 152.9h-1.2v3.4M157.5 159.8h14.9v2.3"/>
<circle cx="166.7" cy="107.2" r=".21"/>
</g>
<circle cx="218.1" cy="114.1" r=".21" fill="#0dab76"/>
<g fill="none" stroke="#0dab76" stroke-width=".13">
<path d="M193 50.1v14.9M106.1 75.2h9.1v2.3M221.5 70.7v2.2h-12.6M205.5 93.5v6.9h4.6v-5.7M118.7 148.3h14.8v1.2M127.8 148.3v1.2"/>
<circle cx="218.1" cy="114.1" r=".21"/>
</g>
<circle cx="127.8" cy="148.3" r=".21" fill="#0dab76"/>
<g fill="none" stroke="#0dab76" stroke-width=".13">
<path d="M133.5 144.9v3.4"/>
<circle cx="127.8" cy="148.3" r=".21"/>
</g>
<circle cx="133.5" cy="148.3" r=".21" fill="#0dab76"/>
<g fill="none" stroke="#0dab76" stroke-width=".13">
<path d="M175.8 80.9v1.2h13.7M157.5 108.4v2.3M166.7 102.7v-2.3h18.3v2.3M179.2 100.4v2.3"/>
<circle cx="133.5" cy="148.3" r=".21"/>
</g>
<circle cx="179.2" cy="100.4" r=".21" fill="#0dab76"/>
<g fill="none" stroke="#0dab76" stroke-width=".13">
<path d="M172.4 100.4v2.3"/>
<circle cx="179.2" cy="100.4" r=".21"/>
</g>
<circle cx="172.4" cy="100.4" r=".21" fill="#0dab76"/>
<g fill="none" stroke="#0dab76" stroke-width=".13">
<path d="M166.7 96.9v3.5"/>
<circle cx="172.4" cy="100.4" r=".21"/>
</g>
<circle cx="166.7" cy="100.4" r=".21" fill="#0dab76"/>
<g fill="none" stroke="#0dab76" stroke-width=".13">
<path d="M109.5 70.7v2.2h-3.4M159.8 62.7v4.5h4.6M237.5 114.1v5.7h-4.6M177 138.1v3.4h6.8M110.7 148.3h-6.9v1.2M167.8 151.8v9.1h-10.3"/>
<circle cx="166.7" cy="100.4" r=".21"/>
</g>
<circle cx="103.8" cy="148.3" r=".21" fill="#0dab76"/>
<g fill="none" stroke="#0dab76" stroke-width=".13">
<path d="M103.8 144.9v3.4M107.2 148.3v2.3h3.5"/>
<circle cx="103.8" cy="148.3" r=".21"/>
</g>
<circle cx="107.2" cy="148.3" r=".21" fill="#0dab76"/>
<g fill="none" stroke="#0dab76" stroke-width=".13">
<path d="M198.7 51.3h4.5v3.4h-5.7v10.3M169 67.2h2.2M215.8 114.1v5.7h4.5M232.9 122.1h4.6M232.9 124.4h4.6M103.8 148.3h-5.7v1.2M157.5 148.3h6.9M157.5 147.2h6.9M170.1 151.8v6.8h-12.6"/>
<circle cx="107.2" cy="148.3" r=".21"/>
</g>
<use href="#words"/>
</svg>
